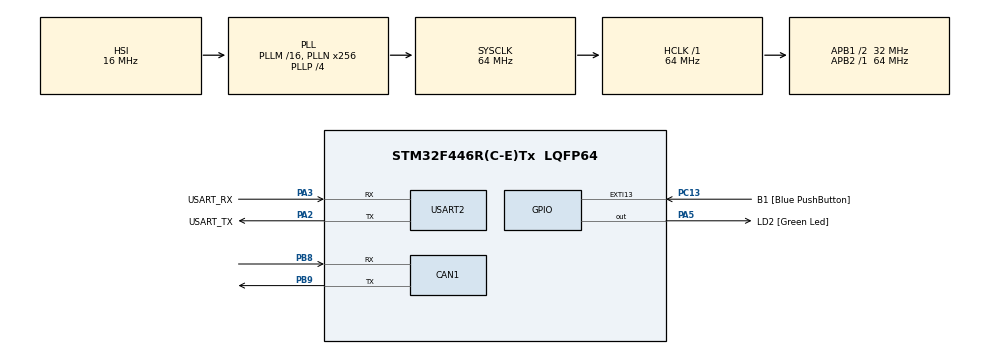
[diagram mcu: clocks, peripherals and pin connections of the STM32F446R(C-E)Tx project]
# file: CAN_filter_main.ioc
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CAN1.CalculateTimeQuantum=500.0
Mcu.Family=STM32F4
Mcu.Name=STM32F446R(C-E)Tx
Mcu.Package=LQFP64
NVIC.PriorityGroup=NVIC_PRIORITYGROUP_0
PA13.GPIO_Label=TMS
PA13.Mode=Serial_Wire
PA13.Signal=SYS_JTMS-SWDIO
PA14.GPIO_Label=TCK
PA14.Mode=Serial_Wire
PA14.Signal=SYS_JTCK-SWCLK
PA2.GPIO_Label=USART_TX
PA2.Mode=Asynchronous
PA2.Signal=USART2_TX
PA3.GPIO_Label=USART_RX
PA3.Mode=Asynchronous
PA3.Signal=USART2_RX
PA5.GPIO_Label=LD2 [Green Led]
PA5.Signal=GPIO_Output
PB3.GPIO_Label=SWO
PB3.Signal=SYS_JTDO-SWO
PB8.Mode=Master
PB8.Signal=CAN1_RX
PB9.Mode=Master
PB9.Signal=CAN1_TX
PC13.GPIO_Label=B1 [Blue PushButton]
PC13.GPIO_ModeDefaultEXTI=GPIO_MODE_IT_FALLING
PC13.Signal=GPXTI13
PC14-OSC32_IN.Mode=LSE-External-Oscillator
PC14-OSC32_IN.Signal=RCC_OSC32_IN
PC15-OSC32_OUT.Mode=LSE-External-Oscillator
PC15-OSC32_OUT.Signal=RCC_OSC32_OUT
PH0-OSC_IN.Mode=HSE-External-Oscillator
PH0-OSC_IN.Signal=RCC_OSC_IN
PH1-OSC_OUT.Mode=HSE-External-Oscillator
PH1-OSC_OUT.Signal=RCC_OSC_OUT
ProjectManager.HeapSize=0x200
ProjectManager.StackSize=0x400
ProjectManager.TargetToolchain=SW4STM32
RCC.48MHZClocksFreq_Value=84000000
RCC.AHBFreq_Value=64000000
RCC.APB1CLKDivider=RCC_HCLK_DIV2
RCC.APB1Freq_Value=32000000
RCC.APB1TimFreq_Value=64000000
RCC.APB2Freq_Value=64000000
RCC.APB2TimFreq_Value=64000000
RCC.CortexFreq_Value=64000000
RCC.FLatency-AdvancedSettings=FLASH_LATENCY_2
RCC.HCLKFreq_Value=64000000
RCC.HSE_VALUE=8000000
RCC.HSI_VALUE=16000000
RCC.PLLN=256
RCC.PLLP=RCC_PLLP_DIV4
RCC.SYSCLKFreq_VALUE=64000000
RCC.SYSCLKSource=RCC_SYSCLKSOURCE_PLLCLK
RCC.USBFreq_Value=128000000
RCC.VCOOutputFreq_Value=256000000
USART2.VirtualMode=VM_ASYNC
board=NUCLEO-F446RE

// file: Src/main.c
/* USER CODE BEGIN Header */
/**
  ******************************************************************************
  * @file           : main.c
  * @brief          : Main program body
  ******************************************************************************
  * @attention
  *
  * <h2><center>&copy; Copyright (c) 2019 STMicroelectronics.
  * All rights reserved.</center></h2>
  *
  * This software component is licensed by ST under BSD 3-Clause license,
  * the "License"; You may not use this file except in compliance with the
  * License. You may obtain a copy of the License at:
  *                        opensource.org/licenses/BSD-3-Clause
  *
  ******************************************************************************
  */
/* USER CODE END Header */

#include "main.h"

CAN_HandleTypeDef hcan1;
CAN_FilterTypeDef sFilterConfig1;
CAN_TxHeaderTypeDef pHeader1;
CAN_RxHeaderTypeDef pHeader2;
UART_HandleTypeDef huart2;

void SystemClock_Config(void);
static void MX_GPIO_Init(void);
static void MX_CAN1_Init(void);
static void MX_USART2_UART_Init(void);

/* USER CODE BEGIN 0 */
uint8_t tx[8];
uint8_t rx[8];
/* USER CODE END 0 */

int main(void)
{

  /* MCU Configuration--------------------------------------------------------*/

  /* Reset of all peripherals, Initializes the Flash interface and the Systick. */
  HAL_Init();

  /* Configure the system clock */
  SystemClock_Config();

  /* Initialize all configured peripherals */
  MX_GPIO_Init();
  MX_CAN1_Init();
  MX_USART2_UART_Init();
  /* USER CODE BEGIN 2 */
  if(HAL_CAN_Start(&hcan1) != HAL_OK)
  {
  	Error_Handler();
  };

	pHeader1.StdId = 0x01;
	pHeader1.ExtId = 0x01;
	pHeader1.DLC = 2;
	tx[0] = 25;
	tx[1] = 21;
	if (HAL_CAN_AddTxMessage(&hcan1, &pHeader1, tx, (uint32_t *)CAN_TX_MAILBOX0) != HAL_OK)
	{
	  Error_Handler();
	}
	HAL_GPIO_WritePin(GPIOA,GPIO_PIN_5,SET);
  /* USER CODE END 2 */

  /* Infinite loop */
  while (1)
  {

    /* USER CODE BEGIN 3 */
	if (HAL_CAN_GetRxFifoFillLevel(&hcan1,CAN_RX_FIFO0) != 0U)
	{
	  if (HAL_CAN_GetRxMessage(&hcan1, CAN_RX_FIFO0, &pHeader2, rx) != HAL_OK)
	  {
		Error_Handler();
	  }
	  pHeader1.StdId = pHeader2.StdId;
	  pHeader1.ExtId = pHeader2.ExtId;
	  pHeader1.DLC = pHeader2.DLC;
	  for(int i=0;i<8;i++){
		  tx[i]=rx[i];
	  }
	  if (HAL_CAN_AddTxMessage(&hcan1, &pHeader1, tx, (uint32_t *)CAN_TX_MAILBOX0) != HAL_OK)
	  {
	    Error_Handler();
	  }

	  HAL_GPIO_WritePin(GPIOA,GPIO_PIN_5,RESET);
	}
	else
	{
	  HAL_GPIO_WritePin(GPIOA,GPIO_PIN_5,SET);
	}
	HAL_Delay(500);
  }
  /* USER CODE END 3 */
}

void SystemClock_Config(void)
{
  RCC_OscInitTypeDef RCC_OscInitStruct = {0};
  RCC_ClkInitTypeDef RCC_ClkInitStruct = {0};

  /** Configure the main internal regulator output voltage
  */
  __HAL_RCC_PWR_CLK_ENABLE();
  __HAL_PWR_VOLTAGESCALING_CONFIG(PWR_REGULATOR_VOLTAGE_SCALE3);
  /** Initializes the CPU, AHB and APB busses clocks
  */
  RCC_OscInitStruct.OscillatorType = RCC_OSCILLATORTYPE_HSI;
  RCC_OscInitStruct.HSIState = RCC_HSI_ON;
  RCC_OscInitStruct.HSICalibrationValue = RCC_HSICALIBRATION_DEFAULT;
  RCC_OscInitStruct.PLL.PLLState = RCC_PLL_ON;
  RCC_OscInitStruct.PLL.PLLSource = RCC_PLLSOURCE_HSI;
  RCC_OscInitStruct.PLL.PLLM = 16;
  RCC_OscInitStruct.PLL.PLLN = 256;
  RCC_OscInitStruct.PLL.PLLP = RCC_PLLP_DIV4;
  RCC_OscInitStruct.PLL.PLLQ = 2;
  RCC_OscInitStruct.PLL.PLLR = 2;
  if (HAL_RCC_OscConfig(&RCC_OscInitStruct) != HAL_OK)
  {
    Error_Handler();
  }
  /** Initializes the CPU, AHB and APB busses clocks
  */
  RCC_ClkInitStruct.ClockType = RCC_CLOCKTYPE_HCLK|RCC_CLOCKTYPE_SYSCLK
                              |RCC_CLOCKTYPE_PCLK1|RCC_CLOCKTYPE_PCLK2;
  RCC_ClkInitStruct.SYSCLKSource = RCC_SYSCLKSOURCE_PLLCLK;
  RCC_ClkInitStruct.AHBCLKDivider = RCC_SYSCLK_DIV1;
  RCC_ClkInitStruct.APB1CLKDivider = RCC_HCLK_DIV2;
  RCC_ClkInitStruct.APB2CLKDivider = RCC_HCLK_DIV1;

  if (HAL_RCC_ClockConfig(&RCC_ClkInitStruct, FLASH_LATENCY_2) != HAL_OK)
  {
    Error_Handler();
  }
}

static void MX_CAN1_Init(void)
{

  hcan1.Instance = CAN1;
  hcan1.Init.Prescaler = 16;
  hcan1.Init.Mode = CAN_MODE_NORMAL;
  hcan1.Init.SyncJumpWidth = CAN_SJW_1TQ;
  hcan1.Init.TimeSeg1 = CAN_BS1_1TQ;
  hcan1.Init.TimeSeg2 = CAN_BS2_1TQ;
  hcan1.Init.TimeTriggeredMode = DISABLE;
  hcan1.Init.AutoBusOff = DISABLE;
  hcan1.Init.AutoWakeUp = DISABLE;
  hcan1.Init.AutoRetransmission = DISABLE;
  hcan1.Init.ReceiveFifoLocked = DISABLE;
  hcan1.Init.TransmitFifoPriority = DISABLE;
  if (HAL_CAN_Init(&hcan1) != HAL_OK)
  {
    Error_Handler();
  }
  /* USER CODE BEGIN CAN1_Init 2 */

  sFilterConfig1.FilterIdHigh = 0x0200;//512(stdId=16)
  sFilterConfig1.FilterIdLow = 0x0000;
  sFilterConfig1.FilterMaskIdHigh = 0xFFE0;
  sFilterConfig1.FilterMaskIdLow = 0x0004;
  sFilterConfig1.FilterMode = CAN_FILTERMODE_IDMASK;
  sFilterConfig1.FilterScale = CAN_FILTERSCALE_32BIT;
  sFilterConfig1.FilterFIFOAssignment = 0;
  sFilterConfig1.FilterActivation = ENABLE;
  if (HAL_CAN_ConfigFilter(&hcan1, &sFilterConfig1) != HAL_OK)
    {
      /* Filter configuration Error */
      Error_Handler();
    }
  pHeader1.IDE = CAN_ID_STD;
  pHeader1.RTR = CAN_RTR_DATA;
  /* USER CODE END CAN1_Init 2 */

}

static void MX_USART2_UART_Init(void)
{

  huart2.Instance = USART2;
  huart2.Init.BaudRate = 115200;
  huart2.Init.WordLength = UART_WORDLENGTH_8B;
  huart2.Init.StopBits = UART_STOPBITS_1;
  huart2.Init.Parity = UART_PARITY_NONE;
  huart2.Init.Mode = UART_MODE_TX_RX;
  huart2.Init.HwFlowCtl = UART_HWCONTROL_NONE;
  huart2.Init.OverSampling = UART_OVERSAMPLING_16;
  if (HAL_UART_Init(&huart2) != HAL_OK)
  {
    Error_Handler();
  }

}

static void MX_GPIO_Init(void)
{
  GPIO_InitTypeDef GPIO_InitStruct = {0};

  /* GPIO Ports Clock Enable */
  __HAL_RCC_GPIOC_CLK_ENABLE();
  __HAL_RCC_GPIOH_CLK_ENABLE();
  __HAL_RCC_GPIOA_CLK_ENABLE();
  __HAL_RCC_GPIOB_CLK_ENABLE();

  /*Configure GPIO pin Output Level */
  HAL_GPIO_WritePin(GPIOA, LD2_Pin|GPIO_PIN_8|GPIO_PIN_9, GPIO_PIN_RESET);

  /*Configure GPIO pin : B1_Pin */
  GPIO_InitStruct.Pin = B1_Pin;
  GPIO_InitStruct.Mode = GPIO_MODE_IT_FALLING;
  GPIO_InitStruct.Pull = GPIO_NOPULL;
  HAL_GPIO_Init(B1_GPIO_Port, &GPIO_InitStruct);

  /*Configure GPIO pins : LD2_Pin PA8 PA9 */
  GPIO_InitStruct.Pin = LD2_Pin|GPIO_PIN_8|GPIO_PIN_9;
  GPIO_InitStruct.Mode = GPIO_MODE_OUTPUT_PP;
  GPIO_InitStruct.Pull = GPIO_NOPULL;
  GPIO_InitStruct.Speed = GPIO_SPEED_FREQ_LOW;
  HAL_GPIO_Init(GPIOA, &GPIO_InitStruct);

}

void Error_Handler(void)
{
}

/************************ (C) COPYRIGHT STMicroelectronics *****END OF FILE****/
